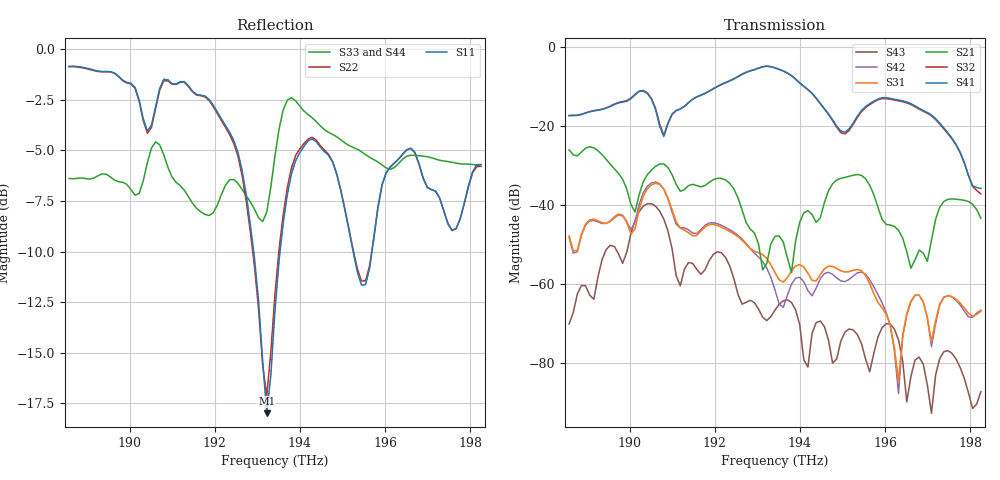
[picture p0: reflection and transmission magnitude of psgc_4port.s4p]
! Created with skrf 1.12.0 (http://scikit-rf.org).
# Hz S RI R 50.0
!freq ReS11 ImS11 ReS12 ImS12 ReS13 ImS13
! ReS14 ImS14
! ReS21 ImS21 ReS22 ImS22 ReS23 ImS23
! ReS24 ImS24
! ReS31 ImS31 ReS32 ImS32 ReS33 ImS33
! ReS34 ImS34
! ReS41 ImS41 ReS42 ImS42 ReS43 ImS43
! ReS44 ImS44
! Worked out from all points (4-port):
!   101 points, 188.58 THz to 198.25 THz, reference 50 ohm
!   strongest paths, dB at 188.58 THz, 191 THz, 193.41 THz, 195.83 THz, 198.25 THz:
!     S41: -17.3, -16.9, -5.1, -13.1, -35.8
!     S32: -17.3, -17.0, -5.2, -13.3, -37.2
!     S21: -26.0, -32.3, -48.0, -40.6, -43.3
!     S31: -47.9, -41.2, -57.1, -64.7, -67.0
!     S42: -48.2, -41.8, -61.6, -62.8, -66.7
!     S43: -70.2, -51.1, -66.7, -73.5, -87.4
!   lowest |S11| = -18.0 dB at 193.22 THz (marker M1), VSWR 1.29, Z = 62.1 - j7.38 ohm
!   |S11| at or under -10 dB: 192.9129 THz to 193.5333 THz (620.4 GHz wide, 0.321 % of centre); 195.2494 THz to 195.6928 THz (443.4 GHz wide, 0.227 % of centre)
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1.885791e14  0.887 0.1903  0.00443 -0.0499  0.000796 -0.00367  0.1246 0.0165
             0.00445 -0.05  0.8844 0.1927  0.1259 0.0162  0.000942 -0.00347
             0.00235 -0.0033  0.1182 0.0695  0.1541 0.4539  -9.15e-05 0.000295
             0.1169 0.0693  0.00241 -0.00303  -9.13e-05 0.000295  0.154 0.454
1.893528e14  -0.1702 0.8645  0.0404 0.0166  0.00847 0.00575  0.047 0.275
             0.0402 0.0167  -0.1736 0.8619  0.0472 0.2772  0.00851 0.00522
             0.00505 0.00319  0.0343 0.1614  0.0685 0.4872  0.0019 0.000693
             0.0335 0.1599  0.00507 0.00287  0.0019 0.000692  0.0685 0.4874
1.904166e14  -0.4816 -0.4029  0.000945 0.0243  -0.0134 -0.00145  -0.2104 -0.056
             0.00105 0.0243  -0.471 -0.4027  -0.2145 -0.0554  -0.0142 -0.00283
             -0.016 0.0014  -0.2649 -0.0156  0.0105 0.5242  0.00253 -0.0101
             -0.2603 -0.0161  -0.0173 -8.96e-05  0.00253 -0.0101  0.0093 0.5275
1.914803e14  0.7632 -0.1923  -0.00528 -0.0174  0.00333 0.00136  -0.1926 -0.0233
             -0.00532 -0.0175  0.7626 -0.181  -0.1937 -0.0253  0.00357 0.00161
             0.00308 0.00264  -0.1982 -0.0969  -0.2201 0.3527  -0.00181 9.87e-05
             -0.1988 -0.0946  0.00323 0.00299  -0.00181 9.9e-05  -0.2189 0.3513
1.932211e14  0.1115 -0.0585  0.00124 0.00129  0.00191 0.0008  0.5584 0.1123
             0.00127 0.00129  0.1333 -0.0397  0.561 0.1238  0.00122 0.00101
             0.00189 0.000905  0.556 0.16  -0.1973 0.3433  -0.00034 -3.38e-05
             0.5609 0.1447  0.00116 0.00108  -0.00034 -3.32e-05  -0.1953 0.3394
1.963157e14  0.1349 0.518  0.00474 0.000583  -3.98e-06 7.96e-05  -0.0559 -0.2837
             0.00474 0.000596  0.1297 0.5195  -0.0539 -0.2769  -2.56e-05 5.15e-05
             6.22e-07 5.79e-05  -0.0533 -0.2032  -0.4663 -0.2339  0.000139 -0.000135
             -0.0544 -0.2083  -1.5e-05 3.74e-05  0.000139 -0.000135  -0.4693 -0.2315
1.982499e14  -0.4132 -0.3145  0.00548 -0.004  0.000384 3.16e-05  0.012 0.00703
             0.00549 -0.00402  -0.407 -0.313  0.00992 0.00673  0.00036 -0.000152
             0.000449 2.44e-07  0.012 0.0069  -0.1629 -0.4874  3.62e-05 -2.33e-05
             0.0145 0.00712  0.000404 -0.000225  3.59e-05 -2.31e-05  -0.1637 -0.4887
